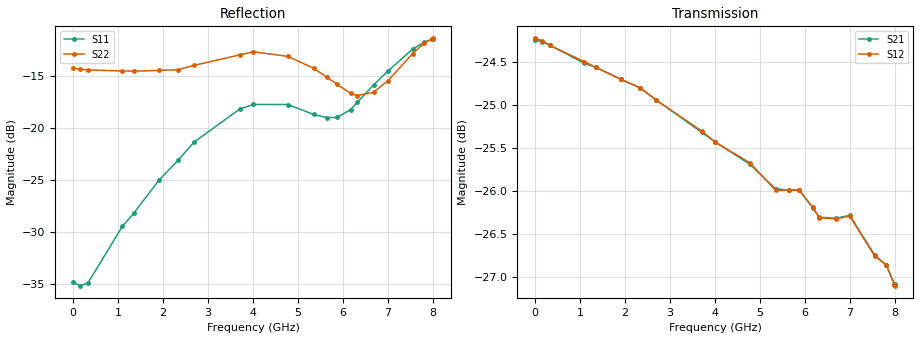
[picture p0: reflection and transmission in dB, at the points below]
! DEVICE ID: PE43712
! File Path: z:\PE43713\PE43713_CHAR_NOM_04292014\AMB\3p300\LS_ATT_23p00dB\PE43713_AMB_3p300V_3p000V_0p000V_LS_ATT_23p00dB_S2P_SN_10_A0139A.s2p
! Serial: 10
! Lot: A0139A
! Temp: 25C
! VDD: 3.300
! VSS: 0.000
! Control_Hi: 3.000
! Control_Lo: 0.000
! Attenuation Step: 23.00dB
! Port 1: RF1
! Port 2: RF2
! ThroughPath:1-2
! IDD: 0.0001471566
! ISS: -1.495e-007
#  Hz  S  RI  R  50
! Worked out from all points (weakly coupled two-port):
!   801 points, 10 MHz to 8.01 GHz, reference 50 ohm
!   highest |S21| = -24.23 dB at 10 MHz (marker M1); lowest = -27.1 dB at 7.99 GHz (marker M2)
!   lowest |S11| = -35.2 dB at 160 MHz (marker M3), VSWR 1.04, Z = 48.4 + j0.522 ohm
!   |S11| at or under -10 dB: start of sweep to end of sweep
!   |S22| runs from -16.9 to -11.3 dB; largest |S21 - S12| = 0.00022
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1e7  -0.018 0.000673  0.0614 -0.000301  0.0615 -0.000286  -0.1948 0.00131
1.6e8  -0.0165 0.0054  0.0611 -0.00362  0.0612 -0.00361  -0.1925 0.0122
3.3e8  -0.015 0.00969  0.0605 -0.00729  0.0605 -0.00723  -0.19 0.0224
1.1e9  -0.01 0.0321  0.0553 -0.0219  0.0554 -0.022  -0.1757 0.0699
1.35e9  -0.0064 0.0383  0.0531 -0.0261  0.0531 -0.0261  -0.1694 0.0831
1.91e9  0.0051 0.0559  0.0469 -0.0345  0.0469 -0.0345  -0.1497 0.1175
2.34e9  0.0167 0.0681  0.0412 -0.0402  0.0412 -0.0402  -0.1313 0.1399
2.68e9  0.0272 0.0809  0.0362 -0.0436  0.0362 -0.0436  -0.1159 0.1642
3.71e9  0.0448 0.1156  0.0195 -0.0506  0.0195 -0.0507  -0.0861 0.2092
4.01e9  0.0473 0.1214  0.0146 -0.0515  0.0146 -0.0515  -0.0837 0.2187
4.78e9  0.0543 0.1183  0.00262 -0.0519  0.00265 -0.052  -0.0661 0.2123
5.35e9  0.0685 0.0943  -0.00534 -0.05  -0.00533 -0.0499  -0.0472 0.1889
5.64e9  0.08 0.0791  -0.00902 -0.0494  -0.00896 -0.0494  -0.0273 0.1746
5.87e9  0.0908 0.0671  -0.0127 -0.0486  -0.0126 -0.0486  -0.00725 0.1628
6.17e9  0.1094 0.056  -0.0175 -0.0458  -0.0174 -0.0459  0.0241 0.1455
6.32e9  0.1227 0.0525  -0.0186 -0.0447  -0.0185 -0.0447  0.0431 0.1373
6.68e9  0.1549 0.0465  -0.0227 -0.0427  -0.0226 -0.0427  0.0881 0.1205
7e9  0.1833 0.0458  -0.0272 -0.0402  -0.0271 -0.0402  0.1243 0.1154
7.55e9  0.2356 0.0518  -0.0325 -0.0326  -0.0324 -0.0326  0.193 0.1243
7.81e9  0.2537 0.058  -0.0341 -0.03  -0.0341 -0.03  0.2215 0.1323
7.99e9  0.263 0.0621  -0.0346 -0.0276  -0.0345 -0.0277  0.2347 0.1349
8.01e9  0.2637 0.0633  -0.0346 -0.0276  -0.0345 -0.0276  0.2359 0.1349
